VERSION 5.7 ;
  NOWIREEXTENSIONATPIN ON ;
  DIVIDERCHAR "/" ;
  BUSBITCHARS "[]" ;
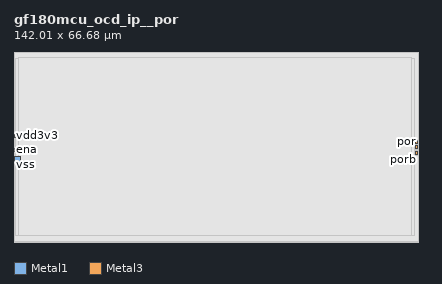
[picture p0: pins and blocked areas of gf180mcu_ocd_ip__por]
MACRO gf180mcu_ocd_ip__por
  CLASS BLOCK ;
  FOREIGN gf180mcu_ocd_ip__por ;
  ORIGIN -40.700 4.600 ;
  SIZE 142.010 BY 66.680 ;
  PIN vdd3v3
    ANTENNAGATEAREA 2.240000 ;
    ANTENNADIFFAREA 97.589447 ;
    PORT
      LAYER Metal1 ;
        RECT 40.900 32.185 42.075 33.235 ;
    END
  END vdd3v3
  PIN ena
    ANTENNAGATEAREA 3.360000 ;
    ANTENNADIFFAREA 0.202500 ;
    PORT
      LAYER Metal3 ;
        RECT 40.890 27.220 41.890 28.220 ;
    END
  END ena
  PIN por_unbuf
    ANTENNAGATEAREA 10.371200 ;
    ANTENNADIFFAREA 0.712200 ;
    PORT
      LAYER Metal3 ;
        RECT 181.475 28.150 182.475 29.150 ;
    END
  END por_unbuf
  PIN vss
    ANTENNAGATEAREA 1.680000 ;
    ANTENNADIFFAREA 363.714355 ;
    PORT
      LAYER Metal1 ;
        RECT 40.935 23.795 42.860 25.235 ;
    END
  END vss
  PIN porb
    ANTENNADIFFAREA 7.461300 ;
    PORT
      LAYER Metal3 ;
        RECT 181.465 26.230 182.465 27.230 ;
    END
  END porb
  PIN por
    ANTENNADIFFAREA 7.461300 ;
    PORT
      LAYER Metal3 ;
        RECT 181.470 30.000 182.470 31.000 ;
    END
  END por
  OBS
      LAYER Pwell ;
        RECT 40.700 33.500 182.660 62.080 ;
      LAYER Nwell ;
        RECT 182.660 33.500 182.710 62.080 ;
        RECT 40.700 -4.600 182.710 33.500 ;
      LAYER Metal1 ;
        RECT 40.885 33.535 182.530 61.895 ;
        RECT 42.375 31.885 182.530 33.535 ;
        RECT 40.885 25.535 182.530 31.885 ;
        RECT 43.160 23.495 182.530 25.535 ;
        RECT 40.885 -4.420 182.530 23.495 ;
      LAYER Metal2 ;
        RECT 40.890 -4.420 182.530 61.890 ;
      LAYER Metal3 ;
        RECT 40.865 31.300 182.590 61.900 ;
        RECT 40.865 29.700 181.170 31.300 ;
        RECT 40.865 29.450 182.590 29.700 ;
        RECT 40.865 28.520 181.175 29.450 ;
        RECT 42.190 27.850 181.175 28.520 ;
        RECT 42.190 27.530 182.590 27.850 ;
        RECT 42.190 26.920 181.165 27.530 ;
        RECT 40.865 25.930 181.165 26.920 ;
        RECT 40.865 -4.415 182.590 25.930 ;
      LAYER Metal4 ;
        RECT 41.195 -2.265 181.230 59.750 ;
      LAYER Metal5 ;
        RECT 42.290 -2.475 180.230 59.975 ;
  END
END gf180mcu_ocd_ip__por
END LIBRARY

